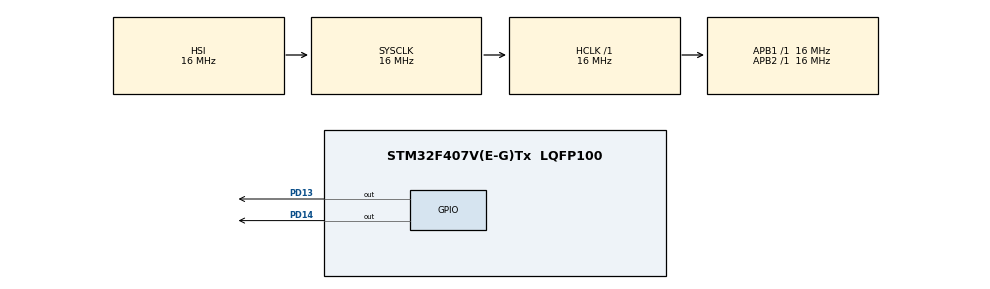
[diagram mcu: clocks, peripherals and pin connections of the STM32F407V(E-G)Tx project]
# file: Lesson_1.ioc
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Mcu.Family=STM32F4
Mcu.Name=STM32F407V(E-G)Tx
Mcu.Package=LQFP100
NVIC.PriorityGroup=NVIC_PRIORITYGROUP_4
PD13.PinState=GPIO_PIN_SET
PD13.Signal=GPIO_Output
PD14.Signal=GPIO_Output
ProjectManager.HeapSize=0x200
ProjectManager.StackSize=0x400
ProjectManager.TargetToolchain=STM32CubeIDE
RCC.AHBFreq_Value=16000000
RCC.APB1Freq_Value=16000000
RCC.APB2Freq_Value=16000000
RCC.CortexFreq_Value=16000000
RCC.HSE_VALUE=25000000
RCC.HSI_VALUE=16000000
RCC.LSE_VALUE=32768
RCC.SYSCLKFreq_VALUE=16000000
RCC.VCOOutputFreq_Value=192000000
board=custom

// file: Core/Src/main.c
/* USER CODE BEGIN Header */
/**
  ******************************************************************************
  * @file           : main.c
  * @brief          : Main program body
  ******************************************************************************
  * @attention
  *
  * <h2><center>&copy; Copyright (c) 2021 STMicroelectronics.
  * All rights reserved.</center></h2>
  *
  * This software component is licensed by ST under BSD 3-Clause license,
  * the "License"; You may not use this file except in compliance with the
  * License. You may obtain a copy of the License at:
  *                        opensource.org/licenses/BSD-3-Clause
  *
  ******************************************************************************
  */
/* USER CODE END Header */
#include "main.h"

void SystemClock_Config(void);
static void MX_GPIO_Init(void);

int main(void)
{

  /* MCU Configuration--------------------------------------------------------*/

  /* Reset of all peripherals, Initializes the Flash interface and the Systick. */
  HAL_Init();

  /* Configure the system clock */
  SystemClock_Config();

  /* Initialize all configured peripherals */
  MX_GPIO_Init();

  /* Infinite loop */
  /* USER CODE BEGIN WHILE */
  while (1)
  {
	  for (int i=0; i<4; i++)
	  {
		  HAL_GPIO_TogglePin (GPIOD, GPIO_PIN_12); 					//inverting the state of the Green LED (On/Off)
		  HAL_Delay(500); 											// wait 0.5 second
		  HAL_GPIO_TogglePin (GPIOD, GPIO_PIN_12| GPIO_PIN_13); 	//inverting the state of the Green LED (Off/On)
		  	  	  	  	  	  	  	  	  	  	  	  	  	  	 	//and Orange LED (On/Off)
		  HAL_Delay(500);
		  HAL_GPIO_TogglePin (GPIOD, GPIO_PIN_13| GPIO_PIN_14);		//inverting the state of the Orange LED (Off/On)
	  	  	  	  	  	 											//and Red LED (On/Off)
		  HAL_Delay(500);
		  HAL_GPIO_TogglePin (GPIOD, GPIO_PIN_14| GPIO_PIN_15);		//inverting the state of the Red LED (Off/On)
																	// and Blue LED (On/Off)
		  HAL_Delay(500);
		  HAL_GPIO_TogglePin (GPIOD, GPIO_PIN_15);					//inverting the state of the Blue Led (Off/On)
	  }
	  HAL_GPIO_TogglePin (GPIOD, GPIO_PIN_15);						//inverting the state of the Blue Led (On/Off)
	  HAL_Delay(500);
	  HAL_GPIO_TogglePin (GPIOD, GPIO_PIN_12);						//inverting the state of the Green Led (On/Off)
	  HAL_Delay(500);
	  HAL_GPIO_TogglePin (GPIOD, GPIO_PIN_13);						//inverting the state of the Orange Led (On/Off)
	  HAL_Delay(500);
	  HAL_GPIO_TogglePin (GPIOD, GPIO_PIN_14);						//inverting the state of the Red Led (On/Off)
	  HAL_Delay(2000);												// wait 2 seconds

    /* USER CODE END WHILE */

  }
}

void SystemClock_Config(void)
{
  RCC_OscInitTypeDef RCC_OscInitStruct = {0};
  RCC_ClkInitTypeDef RCC_ClkInitStruct = {0};

  /** Configure the main internal regulator output voltage
  */
  __HAL_RCC_PWR_CLK_ENABLE();
  __HAL_PWR_VOLTAGESCALING_CONFIG(PWR_REGULATOR_VOLTAGE_SCALE1);
  /** Initializes the RCC Oscillators according to the specified parameters
  * in the RCC_OscInitTypeDef structure.
  */
  RCC_OscInitStruct.OscillatorType = RCC_OSCILLATORTYPE_HSI;
  RCC_OscInitStruct.HSIState = RCC_HSI_ON;
  RCC_OscInitStruct.HSICalibrationValue = RCC_HSICALIBRATION_DEFAULT;
  RCC_OscInitStruct.PLL.PLLState = RCC_PLL_NONE;
  if (HAL_RCC_OscConfig(&RCC_OscInitStruct) != HAL_OK)
  {
    Error_Handler();
  }
  /** Initializes the CPU, AHB and APB buses clocks
  */
  RCC_ClkInitStruct.ClockType = RCC_CLOCKTYPE_HCLK|RCC_CLOCKTYPE_SYSCLK
                              |RCC_CLOCKTYPE_PCLK1|RCC_CLOCKTYPE_PCLK2;
  RCC_ClkInitStruct.SYSCLKSource = RCC_SYSCLKSOURCE_HSI;
  RCC_ClkInitStruct.AHBCLKDivider = RCC_SYSCLK_DIV1;
  RCC_ClkInitStruct.APB1CLKDivider = RCC_HCLK_DIV1;
  RCC_ClkInitStruct.APB2CLKDivider = RCC_HCLK_DIV1;

  if (HAL_RCC_ClockConfig(&RCC_ClkInitStruct, FLASH_LATENCY_0) != HAL_OK)
  {
    Error_Handler();
  }
}

static void MX_GPIO_Init(void)
{
  GPIO_InitTypeDef GPIO_InitStruct = {0};

  /* GPIO Ports Clock Enable */
  __HAL_RCC_GPIOD_CLK_ENABLE();

  /*Configure GPIO pin Output Level */
  HAL_GPIO_WritePin(GPIOD, GPIO_PIN_12, GPIO_PIN_RESET);
  HAL_GPIO_WritePin(GPIOD, GPIO_PIN_13, GPIO_PIN_RESET);
  HAL_GPIO_WritePin(GPIOD, GPIO_PIN_14, GPIO_PIN_RESET);
  HAL_GPIO_WritePin(GPIOD, GPIO_PIN_15, GPIO_PIN_RESET);

  /*Configure GPIO pins : PD13 PD14 */
  GPIO_InitStruct.Pin = GPIO_PIN_13|GPIO_PIN_14|GPIO_PIN_15|GPIO_PIN_12;
  GPIO_InitStruct.Mode = GPIO_MODE_OUTPUT_PP;
  GPIO_InitStruct.Pull = GPIO_NOPULL;
  GPIO_InitStruct.Speed = GPIO_SPEED_FREQ_LOW;
  HAL_GPIO_Init(GPIOD, &GPIO_InitStruct);

}

void Error_Handler(void)
{
  __disable_irq();
  while (1)
  {
  }
}

/************************ (C) COPYRIGHT STMicroelectronics *****END OF FILE****/
